One B-rep face of a CAD part: STEP entity #2519.
In plain terms, the planar face has unit normal (0, 0, 1).
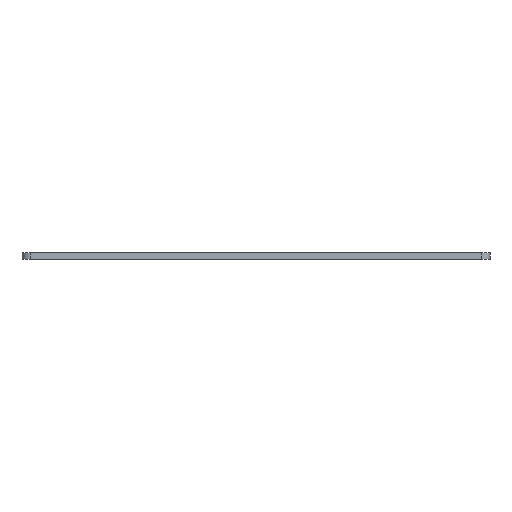
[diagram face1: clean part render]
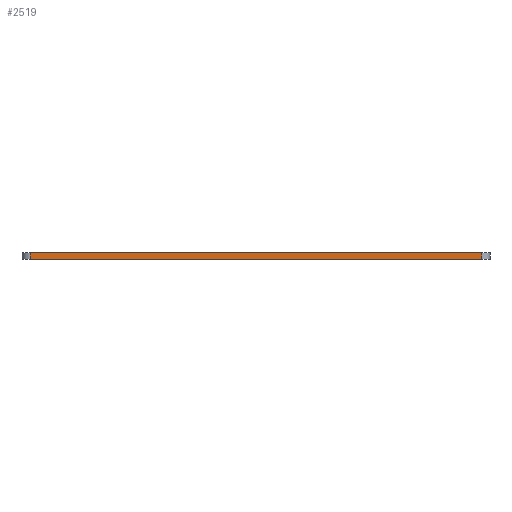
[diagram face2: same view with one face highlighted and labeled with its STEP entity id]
Its self-contained STEP definition (entity closure, numbers rounded to 3 decimals):
#90 = PLANE('',#91);
#91 = AXIS2_PLACEMENT_3D('',#92,#93,#94);
#92 = CARTESIAN_POINT('',(0.,-113.2,61.2));
#93 = DIRECTION('',(0.,-1.,0.));
#94 = DIRECTION('',(1.,0.,0.));
#118 = CYLINDRICAL_SURFACE('',#119,3.);
#119 = AXIS2_PLACEMENT_3D('',#120,#121,#122);
#120 = CARTESIAN_POINT('',(-79.6,-114.4,114.2));
#121 = DIRECTION('',(0.,-1.,0.));
#122 = DIRECTION('',(-1.,0.,0.));
#144 = PLANE('',#145);
#145 = AXIS2_PLACEMENT_3D('',#146,#147,#148);
#146 = CARTESIAN_POINT('',(0.,-115.6,61.2));
#147 = DIRECTION('',(0.,-1.,0.));
#148 = DIRECTION('',(1.,0.,0.));
#332 = VERTEX_POINT('',#333);
#333 = CARTESIAN_POINT('',(79.6,-113.2,117.2));
#352 = CYLINDRICAL_SURFACE('',#353,3.);
#353 = AXIS2_PLACEMENT_3D('',#354,#355,#356);
#354 = CARTESIAN_POINT('',(79.6,-114.4,114.2));
#355 = DIRECTION('',(0.,-1.,0.));
#356 = DIRECTION('',(-1.,0.,0.));
#364 = EDGE_CURVE('',#365,#332,#367,.T.);
#365 = VERTEX_POINT('',#366);
#366 = CARTESIAN_POINT('',(-79.6,-113.2,117.2));
#367 = SURFACE_CURVE('',#368,(#372,#379),.PCURVE_S1.);
#368 = LINE('',#369,#370);
#369 = CARTESIAN_POINT('',(0.,-113.2,117.2));
#370 = VECTOR('',#371,1.);
#371 = DIRECTION('',(1.,0.,0.));
#372 = PCURVE('',#90,#373);
#373 = DEFINITIONAL_REPRESENTATION('',(#374),#378);
#374 = LINE('',#375,#376);
#375 = CARTESIAN_POINT('',(0.,56.));
#376 = VECTOR('',#377,1.);
#377 = DIRECTION('',(1.,0.));
#378 = ( GEOMETRIC_REPRESENTATION_CONTEXT(2) 
PARAMETRIC_REPRESENTATION_CONTEXT() REPRESENTATION_CONTEXT('2D SPACE',''
  ) );
#379 = PCURVE('',#380,#385);
#380 = PLANE('',#381);
#381 = AXIS2_PLACEMENT_3D('',#382,#383,#384);
#382 = CARTESIAN_POINT('',(-79.6,-114.4,117.2));
#383 = DIRECTION('',(0.,0.,-1.));
#384 = DIRECTION('',(1.,0.,0.));
#385 = DEFINITIONAL_REPRESENTATION('',(#386),#390);
#386 = LINE('',#387,#388);
#387 = CARTESIAN_POINT('',(79.6,-1.2));
#388 = VECTOR('',#389,1.);
#389 = DIRECTION('',(1.,0.));
#390 = ( GEOMETRIC_REPRESENTATION_CONTEXT(2) 
PARAMETRIC_REPRESENTATION_CONTEXT() REPRESENTATION_CONTEXT('2D SPACE',''
  ) );
#1459 = VERTEX_POINT('',#1460);
#1460 = CARTESIAN_POINT('',(-79.6,-115.6,117.2));
#1486 = EDGE_CURVE('',#1459,#365,#1487,.T.);
#1487 = SURFACE_CURVE('',#1488,(#1492,#1499),.PCURVE_S1.);
#1488 = LINE('',#1489,#1490);
#1489 = CARTESIAN_POINT('',(-79.6,-115.6,117.2));
#1490 = VECTOR('',#1491,1.);
#1491 = DIRECTION('',(0.,1.,0.));
#1492 = PCURVE('',#118,#1493);
#1493 = DEFINITIONAL_REPRESENTATION('',(#1494),#1498);
#1494 = LINE('',#1495,#1496);
#1495 = CARTESIAN_POINT('',(4.712,1.2));
#1496 = VECTOR('',#1497,1.);
#1497 = DIRECTION('',(0.,-1.));
#1498 = ( GEOMETRIC_REPRESENTATION_CONTEXT(2) 
PARAMETRIC_REPRESENTATION_CONTEXT() REPRESENTATION_CONTEXT('2D SPACE',''
  ) );
#1499 = PCURVE('',#380,#1500);
#1500 = DEFINITIONAL_REPRESENTATION('',(#1501),#1505);
#1501 = LINE('',#1502,#1503);
#1502 = CARTESIAN_POINT('',(0.,1.2));
#1503 = VECTOR('',#1504,1.);
#1504 = DIRECTION('',(0.,-1.));
#1505 = ( GEOMETRIC_REPRESENTATION_CONTEXT(2) 
PARAMETRIC_REPRESENTATION_CONTEXT() REPRESENTATION_CONTEXT('2D SPACE',''
  ) );
#1588 = VERTEX_POINT('',#1589);
#1589 = CARTESIAN_POINT('',(79.6,-115.6,117.2));
#1615 = EDGE_CURVE('',#1459,#1588,#1616,.T.);
#1616 = SURFACE_CURVE('',#1617,(#1621,#1628),.PCURVE_S1.);
#1617 = LINE('',#1618,#1619);
#1618 = CARTESIAN_POINT('',(0.,-115.6,117.2));
#1619 = VECTOR('',#1620,1.);
#1620 = DIRECTION('',(1.,0.,0.));
#1621 = PCURVE('',#144,#1622);
#1622 = DEFINITIONAL_REPRESENTATION('',(#1623),#1627);
#1623 = LINE('',#1624,#1625);
#1624 = CARTESIAN_POINT('',(0.,56.));
#1625 = VECTOR('',#1626,1.);
#1626 = DIRECTION('',(1.,0.));
#1627 = ( GEOMETRIC_REPRESENTATION_CONTEXT(2) 
PARAMETRIC_REPRESENTATION_CONTEXT() REPRESENTATION_CONTEXT('2D SPACE',''
  ) );
#1628 = PCURVE('',#380,#1629);
#1629 = DEFINITIONAL_REPRESENTATION('',(#1630),#1634);
#1630 = LINE('',#1631,#1632);
#1631 = CARTESIAN_POINT('',(79.6,1.2));
#1632 = VECTOR('',#1633,1.);
#1633 = DIRECTION('',(1.,0.));
#1634 = ( GEOMETRIC_REPRESENTATION_CONTEXT(2) 
PARAMETRIC_REPRESENTATION_CONTEXT() REPRESENTATION_CONTEXT('2D SPACE',''
  ) );
#2519 = ADVANCED_FACE('',(#2520),#380,.F.);
#2520 = FACE_BOUND('',#2521,.F.);
#2521 = EDGE_LOOP('',(#2522,#2523,#2544,#2545));
#2522 = ORIENTED_EDGE('',*,*,#364,.T.);
#2523 = ORIENTED_EDGE('',*,*,#2524,.F.);
#2524 = EDGE_CURVE('',#1588,#332,#2525,.T.);
#2525 = SURFACE_CURVE('',#2526,(#2530,#2537),.PCURVE_S1.);
#2526 = LINE('',#2527,#2528);
#2527 = CARTESIAN_POINT('',(79.6,-115.6,117.2));
#2528 = VECTOR('',#2529,1.);
#2529 = DIRECTION('',(0.,1.,0.));
#2530 = PCURVE('',#380,#2531);
#2531 = DEFINITIONAL_REPRESENTATION('',(#2532),#2536);
#2532 = LINE('',#2533,#2534);
#2533 = CARTESIAN_POINT('',(159.2,1.2));
#2534 = VECTOR('',#2535,1.);
#2535 = DIRECTION('',(0.,-1.));
#2536 = ( GEOMETRIC_REPRESENTATION_CONTEXT(2) 
PARAMETRIC_REPRESENTATION_CONTEXT() REPRESENTATION_CONTEXT('2D SPACE',''
  ) );
#2537 = PCURVE('',#352,#2538);
#2538 = DEFINITIONAL_REPRESENTATION('',(#2539),#2543);
#2539 = LINE('',#2540,#2541);
#2540 = CARTESIAN_POINT('',(4.712,1.2));
#2541 = VECTOR('',#2542,1.);
#2542 = DIRECTION('',(0.,-1.));
#2543 = ( GEOMETRIC_REPRESENTATION_CONTEXT(2) 
PARAMETRIC_REPRESENTATION_CONTEXT() REPRESENTATION_CONTEXT('2D SPACE',''
  ) );
#2544 = ORIENTED_EDGE('',*,*,#1615,.F.);
#2545 = ORIENTED_EDGE('',*,*,#1486,.T.);
